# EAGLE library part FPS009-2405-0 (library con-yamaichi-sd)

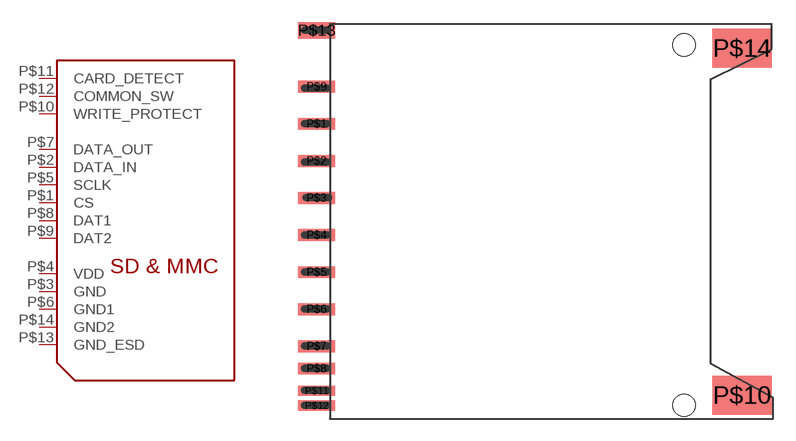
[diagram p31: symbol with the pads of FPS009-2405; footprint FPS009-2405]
Designator prefix SD

## FPS009-2405-0ORIGINAL  [FPS009-2405]
P$1  CS
P$2  DATA_IN
P$3  GND
P$4  VDD
P$5  SCLK
P$6  GND1
P$7  DATA_OUT
P$8  DAT1
P$9  DAT2
P$10  WRITE_PROTECT
P$11  CARD_DETECT
P$12  COMMON_SW
P$13  GND_ESD
P$14  GND2

## FPS009-2405-0"  [FPS009-2405]
P$1  CS
P$2  DATA_IN
P$3  GND
P$4  VDD
P$5  SCLK
P$6  GND1
P$7  DATA_OUT
P$8  WRITE_PROTECT
P$9  DAT2
P$10  DAT1
P$11  CARD_DETECT
P$12  COMMON_SW
P$13  GND_ESD
P$14  GND2

## Footprint FPS009-2405 (pad centres in mm)
smd 2.5 x 0.8: P$1 -14.27,6.88; P$2 -14.27,4.38; P$3 -14.27,1.88; P$4 -14.27,-0.62; P$5 -14.27,-3.12; P$6 -14.27,-5.62; P$7 -14.27,-8.12; P$8 -14.27,-9.62; P$9 -14.27,9.38
smd 4 x 2.65: P$10 14.4,-11.42; P$14 14.4,11.98
smd 2.5 x 0.7: P$11 -14.27,-11.12; P$12 -14.27,-12.12
smd 2.5 x 1.1: P$13 -14.27,13.18
hole 1.5 at 10.5,12.2
hole 1.5 at 10.5,-12.1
